VERSION 5.7 ;
  NOWIREEXTENSIONATPIN ON ;
  DIVIDERCHAR "/" ;
  BUSBITCHARS "[]" ;
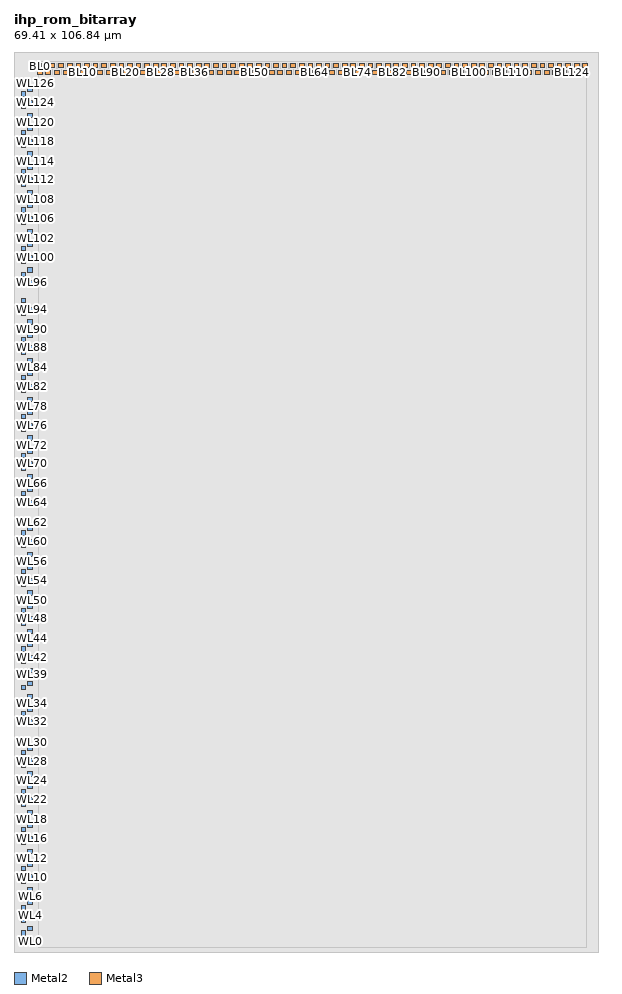
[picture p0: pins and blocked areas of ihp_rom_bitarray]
MACRO ihp_rom_bitarray
  CLASS BLOCK ;
  FOREIGN ihp_rom_bitarray ;
  ORIGIN 2.800 0.990 ;
  SIZE 69.410 BY 106.840 ;
  PIN WL0
    ANTENNAGATEAREA 4.992000 ;
    PORT
      LAYER Metal2 ;
        RECT -1.150 0.005 -0.650 0.505 ;
    END
  END WL0
  PIN WL1
    ANTENNAGATEAREA 4.992000 ;
    PORT
      LAYER Metal2 ;
        RECT -1.950 1.025 -1.450 1.525 ;
    END
  END WL1
  PIN WL2
    ANTENNAGATEAREA 4.992000 ;
    PORT
      LAYER Metal2 ;
        RECT -1.150 1.535 -0.650 2.035 ;
    END
  END WL2
  PIN WL3
    ANTENNAGATEAREA 4.992000 ;
    PORT
      LAYER Metal2 ;
        RECT -1.950 2.555 -1.450 3.055 ;
    END
  END WL3
  PIN WL4
    ANTENNAGATEAREA 4.992000 ;
    PORT
      LAYER Metal2 ;
        RECT -1.150 3.065 -0.650 3.565 ;
    END
  END WL4
  PIN WL5
    ANTENNAGATEAREA 4.992000 ;
    PORT
      LAYER Metal2 ;
        RECT -1.950 4.085 -1.450 4.585 ;
    END
  END WL5
  PIN WL6
    ANTENNAGATEAREA 4.992000 ;
    PORT
      LAYER Metal2 ;
        RECT -1.150 4.595 -0.650 5.095 ;
    END
  END WL6
  PIN WL7
    ANTENNAGATEAREA 4.992000 ;
    PORT
      LAYER Metal2 ;
        RECT -1.950 5.615 -1.450 6.115 ;
    END
  END WL7
  PIN WL8
    ANTENNAGATEAREA 4.992000 ;
    PORT
      LAYER Metal2 ;
        RECT -1.150 6.125 -0.650 6.625 ;
    END
  END WL8
  PIN WL9
    ANTENNAGATEAREA 4.992000 ;
    PORT
      LAYER Metal2 ;
        RECT -1.950 7.145 -1.450 7.645 ;
    END
  END WL9
  PIN WL10
    ANTENNAGATEAREA 4.992000 ;
    PORT
      LAYER Metal2 ;
        RECT -1.150 7.655 -0.650 8.155 ;
    END
  END WL10
  PIN WL11
    ANTENNAGATEAREA 4.992000 ;
    PORT
      LAYER Metal2 ;
        RECT -1.950 8.675 -1.450 9.175 ;
    END
  END WL11
  PIN WL12
    ANTENNAGATEAREA 4.992000 ;
    PORT
      LAYER Metal2 ;
        RECT -1.150 9.185 -0.650 9.685 ;
    END
  END WL12
  PIN WL13
    ANTENNAGATEAREA 4.992000 ;
    PORT
      LAYER Metal2 ;
        RECT -1.950 10.205 -1.450 10.705 ;
    END
  END WL13
  PIN WL14
    ANTENNAGATEAREA 4.992000 ;
    PORT
      LAYER Metal2 ;
        RECT -1.150 10.715 -0.650 11.215 ;
    END
  END WL14
  PIN WL15
    ANTENNAGATEAREA 4.992000 ;
    PORT
      LAYER Metal2 ;
        RECT -1.950 11.735 -1.450 12.235 ;
    END
  END WL15
  PIN WL16
    ANTENNAGATEAREA 4.992000 ;
    PORT
      LAYER Metal2 ;
        RECT -1.150 12.245 -0.650 12.745 ;
    END
  END WL16
  PIN WL17
    ANTENNAGATEAREA 4.992000 ;
    PORT
      LAYER Metal2 ;
        RECT -1.950 13.265 -1.450 13.765 ;
    END
  END WL17
  PIN WL18
    ANTENNAGATEAREA 4.992000 ;
    PORT
      LAYER Metal2 ;
        RECT -1.150 13.775 -0.650 14.275 ;
    END
  END WL18
  PIN WL19
    ANTENNAGATEAREA 4.992000 ;
    PORT
      LAYER Metal2 ;
        RECT -1.950 14.795 -1.450 15.295 ;
    END
  END WL19
  PIN WL20
    ANTENNAGATEAREA 4.992000 ;
    PORT
      LAYER Metal2 ;
        RECT -1.150 15.305 -0.650 15.805 ;
    END
  END WL20
  PIN WL21
    ANTENNAGATEAREA 4.992000 ;
    PORT
      LAYER Metal2 ;
        RECT -1.950 16.325 -1.450 16.825 ;
    END
  END WL21
  PIN WL22
    ANTENNAGATEAREA 4.992000 ;
    PORT
      LAYER Metal2 ;
        RECT -1.150 16.835 -0.650 17.335 ;
    END
  END WL22
  PIN WL23
    ANTENNAGATEAREA 4.992000 ;
    PORT
      LAYER Metal2 ;
        RECT -1.950 17.855 -1.450 18.355 ;
    END
  END WL23
  PIN WL24
    ANTENNAGATEAREA 4.992000 ;
    PORT
      LAYER Metal2 ;
        RECT -1.150 18.365 -0.650 18.865 ;
    END
  END WL24
  PIN WL25
    ANTENNAGATEAREA 4.992000 ;
    PORT
      LAYER Metal2 ;
        RECT -1.950 19.385 -1.450 19.885 ;
    END
  END WL25
  PIN WL26
    ANTENNAGATEAREA 4.992000 ;
    PORT
      LAYER Metal2 ;
        RECT -1.150 19.895 -0.650 20.395 ;
    END
  END WL26
  PIN WL27
    ANTENNAGATEAREA 4.992000 ;
    PORT
      LAYER Metal2 ;
        RECT -1.950 20.915 -1.450 21.415 ;
    END
  END WL27
  PIN WL28
    ANTENNAGATEAREA 4.992000 ;
    PORT
      LAYER Metal2 ;
        RECT -1.150 21.425 -0.650 21.925 ;
    END
  END WL28
  PIN WL29
    ANTENNAGATEAREA 4.992000 ;
    PORT
      LAYER Metal2 ;
        RECT -1.950 22.445 -1.450 22.945 ;
    END
  END WL29
  PIN WL30
    ANTENNAGATEAREA 4.992000 ;
    PORT
      LAYER Metal2 ;
        RECT -1.150 22.955 -0.650 23.455 ;
    END
  END WL30
  PIN WL31
    ANTENNAGATEAREA 4.992000 ;
    PORT
      LAYER Metal2 ;
        RECT -1.950 23.975 -1.450 24.475 ;
    END
  END WL31
  PIN WL32
    ANTENNAGATEAREA 4.992000 ;
    PORT
      LAYER Metal2 ;
        RECT -1.150 26.065 -0.650 26.565 ;
    END
  END WL32
  PIN WL33
    ANTENNAGATEAREA 4.992000 ;
    PORT
      LAYER Metal2 ;
        RECT -1.950 27.085 -1.450 27.585 ;
    END
  END WL33
  PIN WL34
    ANTENNAGATEAREA 4.992000 ;
    PORT
      LAYER Metal2 ;
        RECT -1.150 27.595 -0.650 28.095 ;
    END
  END WL34
  PIN WL35
    ANTENNAGATEAREA 4.992000 ;
    PORT
      LAYER Metal2 ;
        RECT -1.950 28.615 -1.450 29.115 ;
    END
  END WL35
  PIN WL36
    ANTENNAGATEAREA 4.992000 ;
    PORT
      LAYER Metal2 ;
        RECT -1.150 29.125 -0.650 29.625 ;
    END
  END WL36
  PIN WL37
    ANTENNAGATEAREA 4.992000 ;
    PORT
      LAYER Metal2 ;
        RECT -1.950 30.145 -1.450 30.645 ;
    END
  END WL37
  PIN WL38
    ANTENNAGATEAREA 4.992000 ;
    PORT
      LAYER Metal2 ;
        RECT -1.150 30.655 -0.650 31.155 ;
    END
  END WL38
  PIN WL39
    ANTENNAGATEAREA 4.992000 ;
    PORT
      LAYER Metal2 ;
        RECT -1.950 31.675 -1.450 32.175 ;
    END
  END WL39
  PIN WL40
    ANTENNAGATEAREA 4.992000 ;
    PORT
      LAYER Metal2 ;
        RECT -1.150 32.185 -0.650 32.685 ;
    END
  END WL40
  PIN WL41
    ANTENNAGATEAREA 4.992000 ;
    PORT
      LAYER Metal2 ;
        RECT -1.950 33.205 -1.450 33.705 ;
    END
  END WL41
  PIN WL42
    ANTENNAGATEAREA 4.992000 ;
    PORT
      LAYER Metal2 ;
        RECT -1.150 33.715 -0.650 34.215 ;
    END
  END WL42
  PIN WL43
    ANTENNAGATEAREA 4.992000 ;
    PORT
      LAYER Metal2 ;
        RECT -1.950 34.735 -1.450 35.235 ;
    END
  END WL43
  PIN WL44
    ANTENNAGATEAREA 4.992000 ;
    PORT
      LAYER Metal2 ;
        RECT -1.150 35.245 -0.650 35.745 ;
    END
  END WL44
  PIN WL45
    ANTENNAGATEAREA 4.992000 ;
    PORT
      LAYER Metal2 ;
        RECT -1.950 36.265 -1.450 36.765 ;
    END
  END WL45
  PIN WL46
    ANTENNAGATEAREA 4.992000 ;
    PORT
      LAYER Metal2 ;
        RECT -1.150 36.775 -0.650 37.275 ;
    END
  END WL46
  PIN WL47
    ANTENNAGATEAREA 4.992000 ;
    PORT
      LAYER Metal2 ;
        RECT -1.950 37.795 -1.450 38.295 ;
    END
  END WL47
  PIN WL48
    ANTENNAGATEAREA 4.992000 ;
    PORT
      LAYER Metal2 ;
        RECT -1.150 38.305 -0.650 38.805 ;
    END
  END WL48
  PIN WL49
    ANTENNAGATEAREA 4.992000 ;
    PORT
      LAYER Metal2 ;
        RECT -1.950 39.325 -1.450 39.825 ;
    END
  END WL49
  PIN WL50
    ANTENNAGATEAREA 4.992000 ;
    PORT
      LAYER Metal2 ;
        RECT -1.150 39.835 -0.650 40.335 ;
    END
  END WL50
  PIN WL51
    ANTENNAGATEAREA 4.992000 ;
    PORT
      LAYER Metal2 ;
        RECT -1.950 40.855 -1.450 41.355 ;
    END
  END WL51
  PIN WL52
    ANTENNAGATEAREA 4.992000 ;
    PORT
      LAYER Metal2 ;
        RECT -1.150 41.365 -0.650 41.865 ;
    END
  END WL52
  PIN WL53
    ANTENNAGATEAREA 4.992000 ;
    PORT
      LAYER Metal2 ;
        RECT -1.950 42.385 -1.450 42.885 ;
    END
  END WL53
  PIN WL54
    ANTENNAGATEAREA 4.992000 ;
    PORT
      LAYER Metal2 ;
        RECT -1.150 42.895 -0.650 43.395 ;
    END
  END WL54
  PIN WL55
    ANTENNAGATEAREA 4.992000 ;
    PORT
      LAYER Metal2 ;
        RECT -1.950 43.915 -1.450 44.415 ;
    END
  END WL55
  PIN WL56
    ANTENNAGATEAREA 4.992000 ;
    PORT
      LAYER Metal2 ;
        RECT -1.150 44.425 -0.650 44.925 ;
    END
  END WL56
  PIN WL57
    ANTENNAGATEAREA 4.992000 ;
    PORT
      LAYER Metal2 ;
        RECT -1.950 45.445 -1.450 45.945 ;
    END
  END WL57
  PIN WL58
    ANTENNAGATEAREA 4.992000 ;
    PORT
      LAYER Metal2 ;
        RECT -1.150 45.955 -0.650 46.455 ;
    END
  END WL58
  PIN WL59
    ANTENNAGATEAREA 4.992000 ;
    PORT
      LAYER Metal2 ;
        RECT -1.950 46.975 -1.450 47.475 ;
    END
  END WL59
  PIN WL60
    ANTENNAGATEAREA 4.992000 ;
    PORT
      LAYER Metal2 ;
        RECT -1.150 47.485 -0.650 47.985 ;
    END
  END WL60
  PIN WL61
    ANTENNAGATEAREA 4.992000 ;
    PORT
      LAYER Metal2 ;
        RECT -1.950 48.505 -1.450 49.005 ;
    END
  END WL61
  PIN WL62
    ANTENNAGATEAREA 4.992000 ;
    PORT
      LAYER Metal2 ;
        RECT -1.150 49.015 -0.650 49.515 ;
    END
  END WL62
  PIN WL63
    ANTENNAGATEAREA 4.992000 ;
    PORT
      LAYER Metal2 ;
        RECT -1.950 50.035 -1.450 50.535 ;
    END
  END WL63
  PIN WL64
    ANTENNAGATEAREA 4.992000 ;
    PORT
      LAYER Metal2 ;
        RECT -1.150 52.125 -0.650 52.625 ;
    END
  END WL64
  PIN WL65
    ANTENNAGATEAREA 4.992000 ;
    PORT
      LAYER Metal2 ;
        RECT -1.950 53.145 -1.450 53.645 ;
    END
  END WL65
  PIN WL66
    ANTENNAGATEAREA 4.992000 ;
    PORT
      LAYER Metal2 ;
        RECT -1.150 53.655 -0.650 54.155 ;
    END
  END WL66
  PIN WL67
    ANTENNAGATEAREA 4.992000 ;
    PORT
      LAYER Metal2 ;
        RECT -1.950 54.675 -1.450 55.175 ;
    END
  END WL67
  PIN WL68
    ANTENNAGATEAREA 4.992000 ;
    PORT
      LAYER Metal2 ;
        RECT -1.150 55.185 -0.650 55.685 ;
    END
  END WL68
  PIN WL69
    ANTENNAGATEAREA 4.992000 ;
    PORT
      LAYER Metal2 ;
        RECT -1.950 56.205 -1.450 56.705 ;
    END
  END WL69
  PIN WL70
    ANTENNAGATEAREA 4.992000 ;
    PORT
      LAYER Metal2 ;
        RECT -1.150 56.715 -0.650 57.215 ;
    END
  END WL70
  PIN WL71
    ANTENNAGATEAREA 4.992000 ;
    PORT
      LAYER Metal2 ;
        RECT -1.950 57.735 -1.450 58.235 ;
    END
  END WL71
  PIN WL72
    ANTENNAGATEAREA 4.992000 ;
    PORT
      LAYER Metal2 ;
        RECT -1.150 58.245 -0.650 58.745 ;
    END
  END WL72
  PIN WL73
    ANTENNAGATEAREA 4.992000 ;
    PORT
      LAYER Metal2 ;
        RECT -1.950 59.265 -1.450 59.765 ;
    END
  END WL73
  PIN WL74
    ANTENNAGATEAREA 4.992000 ;
    PORT
      LAYER Metal2 ;
        RECT -1.150 59.775 -0.650 60.275 ;
    END
  END WL74
  PIN WL75
    ANTENNAGATEAREA 4.992000 ;
    PORT
      LAYER Metal2 ;
        RECT -1.950 60.795 -1.450 61.295 ;
    END
  END WL75
  PIN WL76
    ANTENNAGATEAREA 4.992000 ;
    PORT
      LAYER Metal2 ;
        RECT -1.150 61.305 -0.650 61.805 ;
    END
  END WL76
  PIN WL77
    ANTENNAGATEAREA 4.992000 ;
    PORT
      LAYER Metal2 ;
        RECT -1.950 62.325 -1.450 62.825 ;
    END
  END WL77
  PIN WL78
    ANTENNAGATEAREA 4.992000 ;
    PORT
      LAYER Metal2 ;
        RECT -1.150 62.835 -0.650 63.335 ;
    END
  END WL78
  PIN WL79
    ANTENNAGATEAREA 4.992000 ;
    PORT
      LAYER Metal2 ;
        RECT -1.950 63.855 -1.450 64.355 ;
    END
  END WL79
  PIN WL80
    ANTENNAGATEAREA 4.992000 ;
    PORT
      LAYER Metal2 ;
        RECT -1.150 64.365 -0.650 64.865 ;
    END
  END WL80
  PIN WL81
    ANTENNAGATEAREA 4.992000 ;
    PORT
      LAYER Metal2 ;
        RECT -1.950 65.385 -1.450 65.885 ;
    END
  END WL81
  PIN WL82
    ANTENNAGATEAREA 4.992000 ;
    PORT
      LAYER Metal2 ;
        RECT -1.150 65.895 -0.650 66.395 ;
    END
  END WL82
  PIN WL83
    ANTENNAGATEAREA 4.992000 ;
    PORT
      LAYER Metal2 ;
        RECT -1.950 66.915 -1.450 67.415 ;
    END
  END WL83
  PIN WL84
    ANTENNAGATEAREA 4.992000 ;
    PORT
      LAYER Metal2 ;
        RECT -1.150 67.425 -0.650 67.925 ;
    END
  END WL84
  PIN WL85
    ANTENNAGATEAREA 4.992000 ;
    PORT
      LAYER Metal2 ;
        RECT -1.950 68.445 -1.450 68.945 ;
    END
  END WL85
  PIN WL86
    ANTENNAGATEAREA 4.992000 ;
    PORT
      LAYER Metal2 ;
        RECT -1.150 68.955 -0.650 69.455 ;
    END
  END WL86
  PIN WL87
    ANTENNAGATEAREA 4.992000 ;
    PORT
      LAYER Metal2 ;
        RECT -1.950 69.975 -1.450 70.475 ;
    END
  END WL87
  PIN WL88
    ANTENNAGATEAREA 4.992000 ;
    PORT
      LAYER Metal2 ;
        RECT -1.150 70.485 -0.650 70.985 ;
    END
  END WL88
  PIN WL89
    ANTENNAGATEAREA 4.992000 ;
    PORT
      LAYER Metal2 ;
        RECT -1.950 71.505 -1.450 72.005 ;
    END
  END WL89
  PIN WL90
    ANTENNAGATEAREA 4.992000 ;
    PORT
      LAYER Metal2 ;
        RECT -1.150 72.015 -0.650 72.515 ;
    END
  END WL90
  PIN WL91
    ANTENNAGATEAREA 4.992000 ;
    PORT
      LAYER Metal2 ;
        RECT -1.950 73.035 -1.450 73.535 ;
    END
  END WL91
  PIN WL92
    ANTENNAGATEAREA 4.992000 ;
    PORT
      LAYER Metal2 ;
        RECT -1.150 73.545 -0.650 74.045 ;
    END
  END WL92
  PIN WL93
    ANTENNAGATEAREA 4.992000 ;
    PORT
      LAYER Metal2 ;
        RECT -1.950 74.565 -1.450 75.065 ;
    END
  END WL93
  PIN WL94
    ANTENNAGATEAREA 4.992000 ;
    PORT
      LAYER Metal2 ;
        RECT -1.150 75.075 -0.650 75.575 ;
    END
  END WL94
  PIN WL95
    ANTENNAGATEAREA 4.992000 ;
    PORT
      LAYER Metal2 ;
        RECT -1.950 76.095 -1.450 76.595 ;
    END
  END WL95
  PIN WL96
    ANTENNAGATEAREA 4.992000 ;
    PORT
      LAYER Metal2 ;
        RECT -1.150 78.185 -0.650 78.685 ;
    END
  END WL96
  PIN WL97
    ANTENNAGATEAREA 4.992000 ;
    PORT
      LAYER Metal2 ;
        RECT -1.950 79.205 -1.450 79.705 ;
    END
  END WL97
  PIN WL98
    ANTENNAGATEAREA 4.992000 ;
    PORT
      LAYER Metal2 ;
        RECT -1.150 79.715 -0.650 80.215 ;
    END
  END WL98
  PIN WL99
    ANTENNAGATEAREA 4.992000 ;
    PORT
      LAYER Metal2 ;
        RECT -1.950 80.735 -1.450 81.235 ;
    END
  END WL99
  PIN WL100
    ANTENNAGATEAREA 4.992000 ;
    PORT
      LAYER Metal2 ;
        RECT -1.150 81.245 -0.650 81.745 ;
    END
  END WL100
  PIN WL101
    ANTENNAGATEAREA 4.992000 ;
    PORT
      LAYER Metal2 ;
        RECT -1.950 82.265 -1.450 82.765 ;
    END
  END WL101
  PIN WL102
    ANTENNAGATEAREA 4.992000 ;
    PORT
      LAYER Metal2 ;
        RECT -1.150 82.775 -0.650 83.275 ;
    END
  END WL102
  PIN WL103
    ANTENNAGATEAREA 4.992000 ;
    PORT
      LAYER Metal2 ;
        RECT -1.950 83.795 -1.450 84.295 ;
    END
  END WL103
  PIN WL104
    ANTENNAGATEAREA 4.992000 ;
    PORT
      LAYER Metal2 ;
        RECT -1.150 84.305 -0.650 84.805 ;
    END
  END WL104
  PIN WL105
    ANTENNAGATEAREA 4.992000 ;
    PORT
      LAYER Metal2 ;
        RECT -1.950 85.325 -1.450 85.825 ;
    END
  END WL105
  PIN WL106
    ANTENNAGATEAREA 4.992000 ;
    PORT
      LAYER Metal2 ;
        RECT -1.150 85.835 -0.650 86.335 ;
    END
  END WL106
  PIN WL107
    ANTENNAGATEAREA 4.992000 ;
    PORT
      LAYER Metal2 ;
        RECT -1.950 86.855 -1.450 87.355 ;
    END
  END WL107
  PIN WL108
    ANTENNAGATEAREA 4.992000 ;
    PORT
      LAYER Metal2 ;
        RECT -1.150 87.365 -0.650 87.865 ;
    END
  END WL108
  PIN WL109
    ANTENNAGATEAREA 4.992000 ;
    PORT
      LAYER Metal2 ;
        RECT -1.950 88.385 -1.450 88.885 ;
    END
  END WL109
  PIN WL110
    ANTENNAGATEAREA 4.992000 ;
    PORT
      LAYER Metal2 ;
        RECT -1.150 88.895 -0.650 89.395 ;
    END
  END WL110
  PIN WL111
    ANTENNAGATEAREA 4.992000 ;
    PORT
      LAYER Metal2 ;
        RECT -1.950 89.915 -1.450 90.415 ;
    END
  END WL111
  PIN WL112
    ANTENNAGATEAREA 4.992000 ;
    PORT
      LAYER Metal2 ;
        RECT -1.150 90.425 -0.650 90.925 ;
    END
  END WL112
  PIN WL113
    ANTENNAGATEAREA 4.992000 ;
    PORT
      LAYER Metal2 ;
        RECT -1.950 91.445 -1.450 91.945 ;
    END
  END WL113
  PIN WL114
    ANTENNAGATEAREA 4.992000 ;
    PORT
      LAYER Metal2 ;
        RECT -1.150 91.955 -0.650 92.455 ;
    END
  END WL114
  PIN WL115
    ANTENNAGATEAREA 4.992000 ;
    PORT
      LAYER Metal2 ;
        RECT -1.950 92.975 -1.450 93.475 ;
    END
  END WL115
  PIN WL116
    ANTENNAGATEAREA 4.992000 ;
    PORT
      LAYER Metal2 ;
        RECT -1.150 93.485 -0.650 93.985 ;
    END
  END WL116
  PIN WL117
    ANTENNAGATEAREA 4.992000 ;
    PORT
      LAYER Metal2 ;
        RECT -1.950 94.505 -1.450 95.005 ;
    END
  END WL117
  PIN WL118
    ANTENNAGATEAREA 4.992000 ;
    PORT
      LAYER Metal2 ;
        RECT -1.150 95.015 -0.650 95.515 ;
    END
  END WL118
  PIN WL119
    ANTENNAGATEAREA 4.992000 ;
    PORT
      LAYER Metal2 ;
        RECT -1.950 96.035 -1.450 96.535 ;
    END
  END WL119
  PIN WL120
    ANTENNAGATEAREA 4.992000 ;
    PORT
      LAYER Metal2 ;
        RECT -1.150 96.545 -0.650 97.045 ;
    END
  END WL120
  PIN WL121
    ANTENNAGATEAREA 4.992000 ;
    PORT
      LAYER Metal2 ;
        RECT -1.950 97.565 -1.450 98.065 ;
    END
  END WL121
  PIN WL122
    ANTENNAGATEAREA 4.992000 ;
    PORT
      LAYER Metal2 ;
        RECT -1.150 98.075 -0.650 98.575 ;
    END
  END WL122
  PIN WL123
    ANTENNAGATEAREA 4.992000 ;
    PORT
      LAYER Metal2 ;
        RECT -1.950 99.095 -1.450 99.595 ;
    END
  END WL123
  PIN WL124
    ANTENNAGATEAREA 4.992000 ;
    PORT
      LAYER Metal2 ;
        RECT -1.150 99.605 -0.650 100.105 ;
    END
  END WL124
  PIN WL125
    ANTENNAGATEAREA 4.992000 ;
    PORT
      LAYER Metal2 ;
        RECT -1.950 100.625 -1.450 101.125 ;
    END
  END WL125
  PIN WL126
    ANTENNAGATEAREA 4.992000 ;
    PORT
      LAYER Metal2 ;
        RECT -1.150 101.135 -0.650 101.635 ;
    END
  END WL126
  PIN WL127
    ANTENNAGATEAREA 4.992000 ;
    PORT
      LAYER Metal2 ;
        RECT -1.950 102.155 -1.450 102.655 ;
    END
  END WL127
  PIN BL0
    ANTENNADIFFAREA 6.630000 ;
    PORT
      LAYER Metal3 ;
        RECT -0.025 103.170 0.535 103.630 ;
    END
  END BL0
  PIN BL1
    ANTENNADIFFAREA 6.426000 ;
    PORT
      LAYER Metal3 ;
        RECT 0.485 103.970 1.045 104.430 ;
    END
  END BL1
  PIN BL2
    ANTENNADIFFAREA 6.426000 ;
    PORT
      LAYER Metal3 ;
        RECT 0.995 103.170 1.555 103.630 ;
    END
  END BL2
  PIN BL3
    ANTENNADIFFAREA 6.630000 ;
    PORT
      LAYER Metal3 ;
        RECT 1.505 103.970 2.065 104.430 ;
    END
  END BL3
  PIN BL4
    ANTENNADIFFAREA 6.426000 ;
    PORT
      LAYER Metal3 ;
        RECT 2.015 103.170 2.575 103.630 ;
    END
  END BL4
  PIN BL5
    ANTENNADIFFAREA 6.426000 ;
    PORT
      LAYER Metal3 ;
        RECT 2.525 103.970 3.085 104.430 ;
    END
  END BL5
  PIN BL6
    ANTENNADIFFAREA 6.630000 ;
    PORT
      LAYER Metal3 ;
        RECT 3.035 103.170 3.595 103.630 ;
    END
  END BL6
  PIN BL7
    ANTENNADIFFAREA 6.426000 ;
    PORT
      LAYER Metal3 ;
        RECT 3.545 103.970 4.105 104.430 ;
    END
  END BL7
  PIN BL8
    ANTENNADIFFAREA 6.426000 ;
    PORT
      LAYER Metal3 ;
        RECT 4.055 103.170 4.615 103.630 ;
    END
  END BL8
  PIN BL9
    ANTENNADIFFAREA 6.630000 ;
    PORT
      LAYER Metal3 ;
        RECT 4.565 103.970 5.125 104.430 ;
    END
  END BL9
  PIN BL10
    ANTENNADIFFAREA 6.630000 ;
    PORT
      LAYER Metal3 ;
        RECT 5.075 103.170 5.635 103.630 ;
    END
  END BL10
  PIN BL11
    ANTENNADIFFAREA 6.426000 ;
    PORT
      LAYER Metal3 ;
        RECT 5.585 103.970 6.145 104.430 ;
    END
  END BL11
  PIN BL12
    ANTENNADIFFAREA 6.630000 ;
    PORT
      LAYER Metal3 ;
        RECT 6.095 103.170 6.655 103.630 ;
    END
  END BL12
  PIN BL13
    ANTENNADIFFAREA 6.630000 ;
    PORT
      LAYER Metal3 ;
        RECT 6.605 103.970 7.165 104.430 ;
    END
  END BL13
  PIN BL14
    ANTENNADIFFAREA 6.426000 ;
    PORT
      LAYER Metal3 ;
        RECT 7.115 103.170 7.675 103.630 ;
    END
  END BL14
  PIN BL15
    ANTENNADIFFAREA 6.630000 ;
    PORT
      LAYER Metal3 ;
        RECT 7.625 103.970 8.185 104.430 ;
    END
  END BL15
  PIN BL16
    ANTENNADIFFAREA 6.426000 ;
    PORT
      LAYER Metal3 ;
        RECT 8.135 103.170 8.695 103.630 ;
    END
  END BL16
  PIN BL17
    ANTENNADIFFAREA 6.630000 ;
    PORT
      LAYER Metal3 ;
        RECT 8.645 103.970 9.205 104.430 ;
    END
  END BL17
  PIN BL18
    ANTENNADIFFAREA 6.630000 ;
    PORT
      LAYER Metal3 ;
        RECT 9.155 103.170 9.715 103.630 ;
    END
  END BL18
  PIN BL19
    ANTENNADIFFAREA 6.426000 ;
    PORT
      LAYER Metal3 ;
        RECT 9.665 103.970 10.225 104.430 ;
    END
  END BL19
  PIN BL20
    ANTENNADIFFAREA 6.630000 ;
    PORT
      LAYER Metal3 ;
        RECT 10.175 103.170 10.735 103.630 ;
    END
  END BL20
  PIN BL21
    ANTENNADIFFAREA 6.630000 ;
    PORT
      LAYER Metal3 ;
        RECT 10.685 103.970 11.245 104.430 ;
    END
  END BL21
  PIN BL22
    ANTENNADIFFAREA 6.426000 ;
    PORT
      LAYER Metal3 ;
        RECT 11.195 103.170 11.755 103.630 ;
    END
  END BL22
  PIN BL23
    ANTENNADIFFAREA 6.630000 ;
    PORT
      LAYER Metal3 ;
        RECT 11.705 103.970 12.265 104.430 ;
    END
  END BL23
  PIN BL24
    ANTENNADIFFAREA 6.630000 ;
    PORT
      LAYER Metal3 ;
        RECT 12.215 103.170 12.775 103.630 ;
    END
  END BL24
  PIN BL25
    ANTENNADIFFAREA 6.426000 ;
    PORT
      LAYER Metal3 ;
        RECT 12.725 103.970 13.285 104.430 ;
    END
  END BL25
  PIN BL26
    ANTENNADIFFAREA 6.426000 ;
    PORT
      LAYER Metal3 ;
        RECT 13.235 103.170 13.795 103.630 ;
    END
  END BL26
  PIN BL27
    ANTENNADIFFAREA 6.630000 ;
    PORT
      LAYER Metal3 ;
        RECT 13.745 103.970 14.305 104.430 ;
    END
  END BL27
  PIN BL28
    ANTENNADIFFAREA 6.426000 ;
    PORT
      LAYER Metal3 ;
        RECT 14.255 103.170 14.815 103.630 ;
    END
  END BL28
  PIN BL29
    ANTENNADIFFAREA 6.426000 ;
    PORT
      LAYER Metal3 ;
        RECT 14.765 103.970 15.325 104.430 ;
    END
  END BL29
  PIN BL30
    ANTENNADIFFAREA 6.630000 ;
    PORT
      LAYER Metal3 ;
        RECT 15.275 103.170 15.835 103.630 ;
    END
  END BL30
  PIN BL31
    ANTENNADIFFAREA 6.426000 ;
    PORT
      LAYER Metal3 ;
        RECT 15.785 103.970 16.345 104.430 ;
    END
  END BL31
  PIN BL32
    ANTENNADIFFAREA 6.630000 ;
    PORT
      LAYER Metal3 ;
        RECT 16.295 103.170 16.855 103.630 ;
    END
  END BL32
  PIN BL33
    ANTENNADIFFAREA 6.426000 ;
    PORT
      LAYER Metal3 ;
        RECT 16.805 103.970 17.365 104.430 ;
    END
  END BL33
  PIN BL34
    ANTENNADIFFAREA 6.426000 ;
    PORT
      LAYER Metal3 ;
        RECT 17.315 103.170 17.875 103.630 ;
    END
  END BL34
  PIN BL35
    ANTENNADIFFAREA 6.630000 ;
    PORT
      LAYER Metal3 ;
        RECT 17.825 103.970 18.385 104.430 ;
    END
  END BL35
  PIN BL36
    ANTENNADIFFAREA 6.426000 ;
    PORT
      LAYER Metal3 ;
        RECT 18.335 103.170 18.895 103.630 ;
    END
  END BL36
  PIN BL37
    ANTENNADIFFAREA 6.426000 ;
    PORT
      LAYER Metal3 ;
        RECT 18.845 103.970 19.405 104.430 ;
    END
  END BL37
  PIN BL38
    ANTENNADIFFAREA 6.630000 ;
    PORT
      LAYER Metal3 ;
        RECT 19.355 103.170 19.915 103.630 ;
    END
  END BL38
  PIN BL39
    ANTENNADIFFAREA 6.426000 ;
    PORT
      LAYER Metal3 ;
        RECT 19.865 103.970 20.425 104.430 ;
    END
  END BL39
  PIN BL40
    ANTENNADIFFAREA 6.426000 ;
    PORT
      LAYER Metal3 ;
        RECT 20.375 103.170 20.935 103.630 ;
    END
  END BL40
  PIN BL41
    ANTENNADIFFAREA 6.630000 ;
    PORT
      LAYER Metal3 ;
        RECT 20.885 103.970 21.445 104.430 ;
    END
  END BL41
  PIN BL42
    ANTENNADIFFAREA 6.630000 ;
    PORT
      LAYER Metal3 ;
        RECT 21.395 103.170 21.955 103.630 ;
    END
  END BL42
  PIN BL43
    ANTENNADIFFAREA 6.426000 ;
    PORT
      LAYER Metal3 ;
        RECT 21.905 103.970 22.465 104.430 ;
    END
  END BL43
  PIN BL44
    ANTENNADIFFAREA 6.630000 ;
    PORT
      LAYER Metal3 ;
        RECT 22.415 103.170 22.975 103.630 ;
    END
  END BL44
  PIN BL45
    ANTENNADIFFAREA 6.630000 ;
    PORT
      LAYER Metal3 ;
        RECT 22.925 103.970 23.485 104.430 ;
    END
  END BL45
  PIN BL46
    ANTENNADIFFAREA 6.426000 ;
    PORT
      LAYER Metal3 ;
        RECT 23.435 103.170 23.995 103.630 ;
    END
  END BL46
  PIN BL47
    ANTENNADIFFAREA 6.630000 ;
    PORT
      LAYER Metal3 ;
        RECT 23.945 103.970 24.505 104.430 ;
    END
  END BL47
  PIN BL48
    ANTENNADIFFAREA 6.426000 ;
    PORT
      LAYER Metal3 ;
        RECT 24.455 103.170 25.015 103.630 ;
    END
  END BL48
  PIN BL49
    ANTENNADIFFAREA 6.630000 ;
    PORT
      LAYER Metal3 ;
        RECT 24.965 103.970 25.525 104.430 ;
    END
  END BL49
  PIN BL50
    ANTENNADIFFAREA 6.630000 ;
    PORT
      LAYER Metal3 ;
        RECT 25.475 103.170 26.035 103.630 ;
    END
  END BL50
  PIN BL51
    ANTENNADIFFAREA 6.426000 ;
    PORT
      LAYER Metal3 ;
        RECT 25.985 103.970 26.545 104.430 ;
    END
  END BL51
  PIN BL52
    ANTENNADIFFAREA 6.630000 ;
    PORT
      LAYER Metal3 ;
        RECT 26.495 103.170 27.055 103.630 ;
    END
  END BL52
  PIN BL53
    ANTENNADIFFAREA 6.630000 ;
    PORT
      LAYER Metal3 ;
        RECT 27.005 103.970 27.565 104.430 ;
    END
  END BL53
  PIN BL54
    ANTENNADIFFAREA 6.426000 ;
    PORT
      LAYER Metal3 ;
        RECT 27.515 103.170 28.075 103.630 ;
    END
  END BL54
  PIN BL55
    ANTENNADIFFAREA 6.630000 ;
    PORT
      LAYER Metal3 ;
        RECT 28.025 103.970 28.585 104.430 ;
    END
  END BL55
  PIN BL56
    ANTENNADIFFAREA 6.630000 ;
    PORT
      LAYER Metal3 ;
        RECT 28.535 103.170 29.095 103.630 ;
    END
  END BL56
  PIN BL57
    ANTENNADIFFAREA 6.426000 ;
    PORT
      LAYER Metal3 ;
        RECT 29.045 103.970 29.605 104.430 ;
    END
  END BL57
  PIN BL58
    ANTENNADIFFAREA 6.426000 ;
    PORT
      LAYER Metal3 ;
        RECT 29.555 103.170 30.115 103.630 ;
    END
  END BL58
  PIN BL59
    ANTENNADIFFAREA 6.630000 ;
    PORT
      LAYER Metal3 ;
        RECT 30.065 103.970 30.625 104.430 ;
    END
  END BL59
  PIN BL60
    ANTENNADIFFAREA 6.426000 ;
    PORT
      LAYER Metal3 ;
        RECT 30.575 103.170 31.135 103.630 ;
    END
  END BL60
  PIN BL61
    ANTENNADIFFAREA 6.426000 ;
    PORT
      LAYER Metal3 ;
        RECT 31.085 103.970 31.645 104.430 ;
    END
  END BL61
  PIN BL62
    ANTENNADIFFAREA 6.630000 ;
    PORT
      LAYER Metal3 ;
        RECT 31.595 103.170 32.155 103.630 ;
    END
  END BL62
  PIN BL63
    ANTENNADIFFAREA 6.426000 ;
    PORT
      LAYER Metal3 ;
        RECT 32.105 103.970 32.665 104.430 ;
    END
  END BL63
  PIN BL64
    ANTENNADIFFAREA 6.630000 ;
    PORT
      LAYER Metal3 ;
        RECT 32.615 103.170 33.175 103.630 ;
    END
  END BL64
  PIN BL65
    ANTENNADIFFAREA 6.426000 ;
    PORT
      LAYER Metal3 ;
        RECT 33.125 103.970 33.685 104.430 ;
    END
  END BL65
  PIN BL66
    ANTENNADIFFAREA 6.426000 ;
    PORT
      LAYER Metal3 ;
        RECT 33.635 103.170 34.195 103.630 ;
    END
  END BL66
  PIN BL67
    ANTENNADIFFAREA 6.630000 ;
    PORT
      LAYER Metal3 ;
        RECT 34.145 103.970 34.705 104.430 ;
    END
  END BL67
  PIN BL68
    ANTENNADIFFAREA 6.426000 ;
    PORT
      LAYER Metal3 ;
        RECT 34.655 103.170 35.215 103.630 ;
    END
  END BL68
  PIN BL69
    ANTENNADIFFAREA 6.426000 ;
    PORT
      LAYER Metal3 ;
        RECT 35.165 103.970 35.725 104.430 ;
    END
  END BL69
  PIN BL70
    ANTENNADIFFAREA 6.630000 ;
    PORT
      LAYER Metal3 ;
        RECT 35.675 103.170 36.235 103.630 ;
    END
  END BL70
  PIN BL71
    ANTENNADIFFAREA 6.426000 ;
    PORT
      LAYER Metal3 ;
        RECT 36.185 103.970 36.745 104.430 ;
    END
  END BL71
  PIN BL72
    ANTENNADIFFAREA 6.426000 ;
    PORT
      LAYER Metal3 ;
        RECT 36.695 103.170 37.255 103.630 ;
    END
  END BL72
  PIN BL73
    ANTENNADIFFAREA 6.630000 ;
    PORT
      LAYER Metal3 ;
        RECT 37.205 103.970 37.765 104.430 ;
    END
  END BL73
  PIN BL74
    ANTENNADIFFAREA 6.630000 ;
    PORT
      LAYER Metal3 ;
        RECT 37.715 103.170 38.275 103.630 ;
    END
  END BL74
  PIN BL75
    ANTENNADIFFAREA 6.426000 ;
    PORT
      LAYER Metal3 ;
        RECT 38.225 103.970 38.785 104.430 ;
    END
  END BL75
  PIN BL76
    ANTENNADIFFAREA 6.630000 ;
    PORT
      LAYER Metal3 ;
        RECT 38.735 103.170 39.295 103.630 ;
    END
  END BL76
  PIN BL77
    ANTENNADIFFAREA 6.630000 ;
    PORT
      LAYER Metal3 ;
        RECT 39.245 103.970 39.805 104.430 ;
    END
  END BL77
  PIN BL78
    ANTENNADIFFAREA 6.426000 ;
    PORT
      LAYER Metal3 ;
        RECT 39.755 103.170 40.315 103.630 ;
    END
  END BL78
  PIN BL79
    ANTENNADIFFAREA 6.630000 ;
    PORT
      LAYER Metal3 ;
        RECT 40.265 103.970 40.825 104.430 ;
    END
  END BL79
  PIN BL80
    ANTENNADIFFAREA 6.426000 ;
    PORT
      LAYER Metal3 ;
        RECT 40.775 103.170 41.335 103.630 ;
    END
  END BL80
  PIN BL81
    ANTENNADIFFAREA 6.630000 ;
    PORT
      LAYER Metal3 ;
        RECT 41.285 103.970 41.845 104.430 ;
    END
  END BL81
  PIN BL82
    ANTENNADIFFAREA 6.630000 ;
    PORT
      LAYER Metal3 ;
        RECT 41.795 103.170 42.355 103.630 ;
    END
  END BL82
  PIN BL83
    ANTENNADIFFAREA 6.426000 ;
    PORT
      LAYER Metal3 ;
        RECT 42.305 103.970 42.865 104.430 ;
    END
  END BL83
  PIN BL84
    ANTENNADIFFAREA 6.630000 ;
    PORT
      LAYER Metal3 ;
        RECT 42.815 103.170 43.375 103.630 ;
    END
  END BL84
  PIN BL85
    ANTENNADIFFAREA 6.630000 ;
    PORT
      LAYER Metal3 ;
        RECT 43.325 103.970 43.885 104.430 ;
    END
  END BL85
  PIN BL86
    ANTENNADIFFAREA 6.426000 ;
    PORT
      LAYER Metal3 ;
        RECT 43.835 103.170 44.395 103.630 ;
    END
  END BL86
  PIN BL87
    ANTENNADIFFAREA 6.630000 ;
    PORT
      LAYER Metal3 ;
        RECT 44.345 103.970 44.905 104.430 ;
    END
  END BL87
  PIN BL88
    ANTENNADIFFAREA 6.630000 ;
    PORT
      LAYER Metal3 ;
        RECT 44.855 103.170 45.415 103.630 ;
    END
  END BL88
  PIN BL89
    ANTENNADIFFAREA 6.426000 ;
    PORT
      LAYER Metal3 ;
        RECT 45.365 103.970 45.925 104.430 ;
    END
  END BL89
  PIN BL90
    ANTENNADIFFAREA 6.426000 ;
    PORT
      LAYER Metal3 ;
        RECT 45.875 103.170 46.435 103.630 ;
    END
  END BL90
  PIN BL91
    ANTENNADIFFAREA 6.630000 ;
    PORT
      LAYER Metal3 ;
        RECT 46.385 103.970 46.945 104.430 ;
    END
  END BL91
  PIN BL92
    ANTENNADIFFAREA 6.426000 ;
    PORT
      LAYER Metal3 ;
        RECT 46.895 103.170 47.455 103.630 ;
    END
  END BL92
  PIN BL93
    ANTENNADIFFAREA 6.426000 ;
    PORT
      LAYER Metal3 ;
        RECT 47.405 103.970 47.965 104.430 ;
    END
  END BL93
  PIN BL94
    ANTENNADIFFAREA 6.630000 ;
    PORT
      LAYER Metal3 ;
        RECT 47.915 103.170 48.475 103.630 ;
    END
  END BL94
  PIN BL95
    ANTENNADIFFAREA 6.426000 ;
    PORT
      LAYER Metal3 ;
        RECT 48.425 103.970 48.985 104.430 ;
    END
  END BL95
  PIN BL96
    ANTENNADIFFAREA 6.630000 ;
    PORT
      LAYER Metal3 ;
        RECT 48.935 103.170 49.495 103.630 ;
    END
  END BL96
  PIN BL97
    ANTENNADIFFAREA 6.426000 ;
    PORT
      LAYER Metal3 ;
        RECT 49.445 103.970 50.005 104.430 ;
    END
  END BL97
  PIN BL98
    ANTENNADIFFAREA 6.426000 ;
    PORT
      LAYER Metal3 ;
        RECT 49.955 103.170 50.515 103.630 ;
    END
  END BL98
  PIN BL99
    ANTENNADIFFAREA 6.630000 ;
    PORT
      LAYER Metal3 ;
        RECT 50.465 103.970 51.025 104.430 ;
    END
  END BL99
  PIN BL100
    ANTENNADIFFAREA 6.426000 ;
    PORT
      LAYER Metal3 ;
        RECT 50.975 103.170 51.535 103.630 ;
    END
  END BL100
  PIN BL101
    ANTENNADIFFAREA 6.426000 ;
    PORT
      LAYER Metal3 ;
        RECT 51.485 103.970 52.045 104.430 ;
    END
  END BL101
  PIN BL102
    ANTENNADIFFAREA 6.630000 ;
    PORT
      LAYER Metal3 ;
        RECT 51.995 103.170 52.555 103.630 ;
    END
  END BL102
  PIN BL103
    ANTENNADIFFAREA 6.426000 ;
    PORT
      LAYER Metal3 ;
        RECT 52.505 103.970 53.065 104.430 ;
    END
  END BL103
  PIN BL104
    ANTENNADIFFAREA 6.426000 ;
    PORT
      LAYER Metal3 ;
        RECT 53.015 103.170 53.575 103.630 ;
    END
  END BL104
  PIN BL105
    ANTENNADIFFAREA 6.630000 ;
    PORT
      LAYER Metal3 ;
        RECT 53.525 103.970 54.085 104.430 ;
    END
  END BL105
  PIN BL106
    ANTENNADIFFAREA 6.426000 ;
    PORT
      LAYER Metal3 ;
        RECT 54.035 103.170 54.595 103.630 ;
    END
  END BL106
  PIN BL107
    ANTENNADIFFAREA 6.426000 ;
    PORT
      LAYER Metal3 ;
        RECT 54.545 103.970 55.105 104.430 ;
    END
  END BL107
  PIN BL108
    ANTENNADIFFAREA 6.630000 ;
    PORT
      LAYER Metal3 ;
        RECT 55.055 103.170 55.615 103.630 ;
    END
  END BL108
  PIN BL109
    ANTENNADIFFAREA 6.630000 ;
    PORT
      LAYER Metal3 ;
        RECT 55.565 103.970 56.125 104.430 ;
    END
  END BL109
  PIN BL110
    ANTENNADIFFAREA 6.426000 ;
    PORT
      LAYER Metal3 ;
        RECT 56.075 103.170 56.635 103.630 ;
    END
  END BL110
  PIN BL111
    ANTENNADIFFAREA 6.630000 ;
    PORT
      LAYER Metal3 ;
        RECT 56.585 103.970 57.145 104.430 ;
    END
  END BL111
  PIN BL112
    ANTENNADIFFAREA 6.426000 ;
    PORT
      LAYER Metal3 ;
        RECT 57.095 103.170 57.655 103.630 ;
    END
  END BL112
  PIN BL113
    ANTENNADIFFAREA 6.630000 ;
    PORT
      LAYER Metal3 ;
        RECT 57.605 103.970 58.165 104.430 ;
    END
  END BL113
  PIN BL114
    ANTENNADIFFAREA 6.426000 ;
    PORT
      LAYER Metal3 ;
        RECT 58.115 103.170 58.675 103.630 ;
    END
  END BL114
  PIN BL115
    ANTENNADIFFAREA 6.426000 ;
    PORT
      LAYER Metal3 ;
        RECT 58.625 103.970 59.185 104.430 ;
    END
  END BL115
  PIN BL116
    ANTENNADIFFAREA 6.630000 ;
    PORT
      LAYER Metal3 ;
        RECT 59.135 103.170 59.695 103.630 ;
    END
  END BL116
  PIN BL117
    ANTENNADIFFAREA 6.630000 ;
    PORT
      LAYER Metal3 ;
        RECT 59.645 103.970 60.205 104.430 ;
    END
  END BL117
  PIN BL118
    ANTENNADIFFAREA 6.426000 ;
    PORT
      LAYER Metal3 ;
        RECT 60.155 103.170 60.715 103.630 ;
    END
  END BL118
  PIN BL119
    ANTENNADIFFAREA 6.630000 ;
    PORT
      LAYER Metal3 ;
        RECT 60.665 103.970 61.225 104.430 ;
    END
  END BL119
  PIN BL120
    ANTENNADIFFAREA 6.630000 ;
    PORT
      LAYER Metal3 ;
        RECT 61.175 103.170 61.735 103.630 ;
    END
  END BL120
  PIN BL121
    ANTENNADIFFAREA 6.426000 ;
    PORT
      LAYER Metal3 ;
        RECT 61.685 103.970 62.245 104.430 ;
    END
  END BL121
  PIN BL122
    ANTENNADIFFAREA 6.630000 ;
    PORT
      LAYER Metal3 ;
        RECT 62.195 103.170 62.755 103.630 ;
    END
  END BL122
  PIN BL123
    ANTENNADIFFAREA 6.630000 ;
    PORT
      LAYER Metal3 ;
        RECT 62.705 103.970 63.265 104.430 ;
    END
  END BL123
  PIN BL124
    ANTENNADIFFAREA 6.426000 ;
    PORT
      LAYER Metal3 ;
        RECT 63.215 103.170 63.775 103.630 ;
    END
  END BL124
  PIN BL125
    ANTENNADIFFAREA 6.426000 ;
    PORT
      LAYER Metal3 ;
        RECT 63.725 103.970 64.285 104.430 ;
    END
  END BL125
  PIN BL126
    ANTENNADIFFAREA 6.630000 ;
    PORT
      LAYER Metal3 ;
        RECT 64.235 103.170 64.795 103.630 ;
    END
  END BL126
  PIN BL127
    ANTENNADIFFAREA 6.426000 ;
    PORT
      LAYER Metal3 ;
        RECT 64.745 103.970 65.305 104.430 ;
    END
  END BL127
  OBS
      LAYER GatPoly ;
        RECT -2.800 -0.990 66.610 105.850 ;
      LAYER Metal1 ;
        RECT -2.800 -0.990 66.610 105.850 ;
      LAYER Metal2 ;
        RECT 0.105 -0.490 65.175 104.750 ;
      LAYER Metal3 ;
        RECT -0.045 103.840 0.275 104.450 ;
        RECT 1.255 103.840 1.295 104.450 ;
        RECT 2.275 103.840 2.315 104.450 ;
        RECT 3.295 103.840 3.335 104.450 ;
        RECT 4.315 103.840 4.355 104.450 ;
        RECT 5.335 103.840 5.375 104.450 ;
        RECT 6.355 103.840 6.395 104.450 ;
        RECT 7.375 103.840 7.415 104.450 ;
        RECT 8.395 103.840 8.435 104.450 ;
        RECT 9.415 103.840 9.455 104.450 ;
        RECT 10.435 103.840 10.475 104.450 ;
        RECT 11.455 103.840 11.495 104.450 ;
        RECT 12.475 103.840 12.515 104.450 ;
        RECT 13.495 103.840 13.535 104.450 ;
        RECT 14.515 103.840 14.555 104.450 ;
        RECT 15.535 103.840 15.575 104.450 ;
        RECT 16.555 103.840 16.595 104.450 ;
        RECT 17.575 103.840 17.615 104.450 ;
        RECT 18.595 103.840 18.635 104.450 ;
        RECT 19.615 103.840 19.655 104.450 ;
        RECT 20.635 103.840 20.675 104.450 ;
        RECT 21.655 103.840 21.695 104.450 ;
        RECT 22.675 103.840 22.715 104.450 ;
        RECT 23.695 103.840 23.735 104.450 ;
        RECT 24.715 103.840 24.755 104.450 ;
        RECT 25.735 103.840 25.775 104.450 ;
        RECT 26.755 103.840 26.795 104.450 ;
        RECT 27.775 103.840 27.815 104.450 ;
        RECT 28.795 103.840 28.835 104.450 ;
        RECT 29.815 103.840 29.855 104.450 ;
        RECT 30.835 103.840 30.875 104.450 ;
        RECT 31.855 103.840 31.895 104.450 ;
        RECT 32.875 103.840 32.915 104.450 ;
        RECT 33.895 103.840 33.935 104.450 ;
        RECT 34.915 103.840 34.955 104.450 ;
        RECT 35.935 103.840 35.975 104.450 ;
        RECT 36.955 103.840 36.995 104.450 ;
        RECT 37.975 103.840 38.015 104.450 ;
        RECT 38.995 103.840 39.035 104.450 ;
        RECT 40.015 103.840 40.055 104.450 ;
        RECT 41.035 103.840 41.075 104.450 ;
        RECT 42.055 103.840 42.095 104.450 ;
        RECT 43.075 103.840 43.115 104.450 ;
        RECT 44.095 103.840 44.135 104.450 ;
        RECT 45.115 103.840 45.155 104.450 ;
        RECT 46.135 103.840 46.175 104.450 ;
        RECT 47.155 103.840 47.195 104.450 ;
        RECT 48.175 103.840 48.215 104.450 ;
        RECT 49.195 103.840 49.235 104.450 ;
        RECT 50.215 103.840 50.255 104.450 ;
        RECT 51.235 103.840 51.275 104.450 ;
        RECT 52.255 103.840 52.295 104.450 ;
        RECT 53.275 103.840 53.315 104.450 ;
        RECT 54.295 103.840 54.335 104.450 ;
        RECT 55.315 103.840 55.355 104.450 ;
        RECT 56.335 103.840 56.375 104.450 ;
        RECT 57.355 103.840 57.395 104.450 ;
        RECT 58.375 103.840 58.415 104.450 ;
        RECT 59.395 103.840 59.435 104.450 ;
        RECT 60.415 103.840 60.455 104.450 ;
        RECT 61.435 103.840 61.475 104.450 ;
        RECT 62.455 103.840 62.495 104.450 ;
        RECT 63.475 103.840 63.515 104.450 ;
        RECT 64.495 103.840 64.535 104.450 ;
        RECT 0.745 103.150 0.785 103.760 ;
        RECT 1.765 103.150 1.805 103.760 ;
        RECT 2.785 103.150 2.825 103.760 ;
        RECT 3.805 103.150 3.845 103.760 ;
        RECT 4.825 103.150 4.865 103.760 ;
        RECT 5.845 103.150 5.885 103.760 ;
        RECT 6.865 103.150 6.905 103.760 ;
        RECT 7.885 103.150 7.925 103.760 ;
        RECT 8.905 103.150 8.945 103.760 ;
        RECT 9.925 103.150 9.965 103.760 ;
        RECT 10.945 103.150 10.985 103.760 ;
        RECT 11.965 103.150 12.005 103.760 ;
        RECT 12.985 103.150 13.025 103.760 ;
        RECT 14.005 103.150 14.045 103.760 ;
        RECT 15.025 103.150 15.065 103.760 ;
        RECT 16.045 103.150 16.085 103.760 ;
        RECT 17.065 103.150 17.105 103.760 ;
        RECT 18.085 103.150 18.125 103.760 ;
        RECT 19.105 103.150 19.145 103.760 ;
        RECT 20.125 103.150 20.165 103.760 ;
        RECT 21.145 103.150 21.185 103.760 ;
        RECT 22.165 103.150 22.205 103.760 ;
        RECT 23.185 103.150 23.225 103.760 ;
        RECT 24.205 103.150 24.245 103.760 ;
        RECT 25.225 103.150 25.265 103.760 ;
        RECT 26.245 103.150 26.285 103.760 ;
        RECT 27.265 103.150 27.305 103.760 ;
        RECT 28.285 103.150 28.325 103.760 ;
        RECT 29.305 103.150 29.345 103.760 ;
        RECT 30.325 103.150 30.365 103.760 ;
        RECT 31.345 103.150 31.385 103.760 ;
        RECT 32.365 103.150 32.405 103.760 ;
        RECT 33.385 103.150 33.425 103.760 ;
        RECT 34.405 103.150 34.445 103.760 ;
        RECT 35.425 103.150 35.465 103.760 ;
        RECT 36.445 103.150 36.485 103.760 ;
        RECT 37.465 103.150 37.505 103.760 ;
        RECT 38.485 103.150 38.525 103.760 ;
        RECT 39.505 103.150 39.545 103.760 ;
        RECT 40.525 103.150 40.565 103.760 ;
        RECT 41.545 103.150 41.585 103.760 ;
        RECT 42.565 103.150 42.605 103.760 ;
        RECT 43.585 103.150 43.625 103.760 ;
        RECT 44.605 103.150 44.645 103.760 ;
        RECT 45.625 103.150 45.665 103.760 ;
        RECT 46.645 103.150 46.685 103.760 ;
        RECT 47.665 103.150 47.705 103.760 ;
        RECT 48.685 103.150 48.725 103.760 ;
        RECT 49.705 103.150 49.745 103.760 ;
        RECT 50.725 103.150 50.765 103.760 ;
        RECT 51.745 103.150 51.785 103.760 ;
        RECT 52.765 103.150 52.805 103.760 ;
        RECT 53.785 103.150 53.825 103.760 ;
        RECT 54.805 103.150 54.845 103.760 ;
        RECT 55.825 103.150 55.865 103.760 ;
        RECT 56.845 103.150 56.885 103.760 ;
        RECT 57.865 103.150 57.905 103.760 ;
        RECT 58.885 103.150 58.925 103.760 ;
        RECT 59.905 103.150 59.945 103.760 ;
        RECT 60.925 103.150 60.965 103.760 ;
        RECT 61.945 103.150 61.985 103.760 ;
        RECT 62.965 103.150 63.005 103.760 ;
        RECT 63.985 103.150 64.025 103.760 ;
        RECT 65.005 103.150 65.325 103.760 ;
  END
END ihp_rom_bitarray
END LIBRARY

